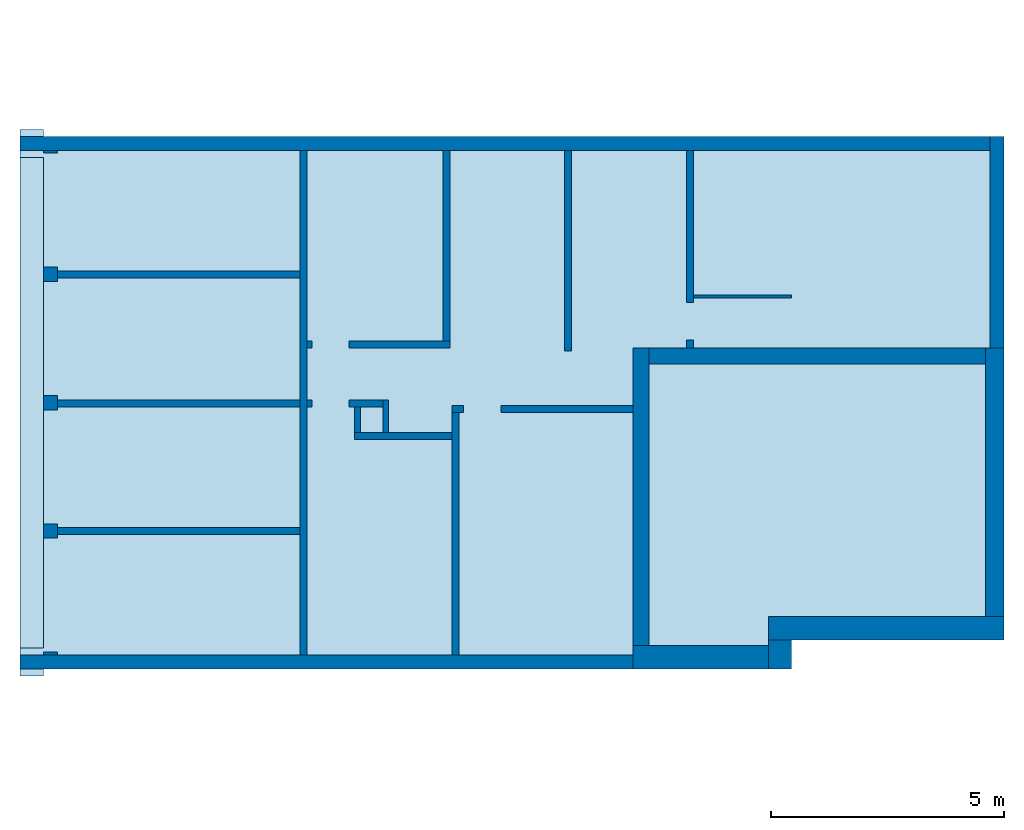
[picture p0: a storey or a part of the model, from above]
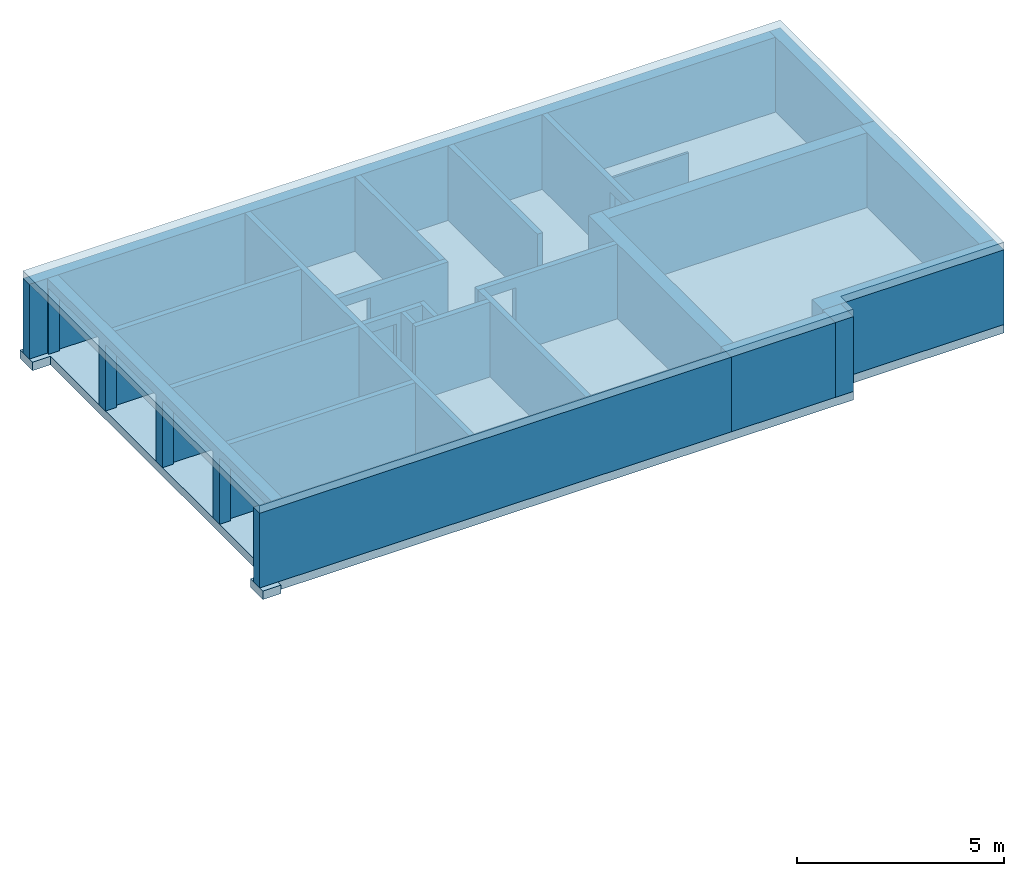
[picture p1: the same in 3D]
Properties of the parts of a building model (IFC2X3)

# File
Description: no view
File name: H.ifc
Time: 2026-08-27T15:52:09
Author: Besar Asani
Organization: No Organization
Written by: ODA SDAI 25.4
Authorization: b.asani

# IfcProject, 00'000 - Besar Asani
AllplanAttributes - Bauherr: Bauherr Name; Architekt: Architekt Name; Bauort: PLZ und Ort; Bauunternehmer Straße: Bauunternehmer Strasse; Bauunternehmer Plz/Ort: Bauunternehmer PLZ Ort; Bauherr Straße: Bauherr Strasse; Bauherr Plz/Ort: Bauherr PLZ Ort; Architekt Straße: Architekt Strasse; Architekt Plz/Ort: Architekt PLZ Ort; Projektbeschreibung: Projektbeschreibung; Bauunternehmer: Bauunternehmer Name

# IfcSite, Modelle auf dem Nullpunkt
RefLatitude: 48, 8, 10, 320000; RefLongitude: 11, 41, 19, 320000

# IfcBuildingStorey (2)
In: H
Elevation: 0 m
Name
UG
EG

# IfcBuildingElementProxy (2)
In: UG
AllplanAttributes - Objektname: Kontrollpunkt; Bezeichnung: Kontrollpunkt; Typ: Kontrollpunkt; Elementbezeichnung: Kontrollpunkt; Barrierefrei: no; öffentlich zugänglich: no; Attributset-Objekt: Body; Abrechnungsart: m³
BuildingElementProxyCommon - Status: Neubau; Tragendes Bauteil: no
Name | Text1 | Text2 | Allright_Bauteil_ID
Kontrollpunkt | X = 2695854.80 | Y = 1261037.75 | 7501Kop0000000102
Kontrollpunkt | X = 2695821.05 | Y = 1261022.70 | 7501Kop0000000104 | AllplanAttributes - X_Koordinate: 0 m; Y_Koordinate: 0 m; Achsenendpunkt (X): 0 m

# IfcOpeningElement: Opening (25)
AllplanAttributes - Object Layer Attributes #1, Türanschlag: -; Object Layer Attributes #1, Objektname: Türöffnung; Object Layer Attributes #1, Abrechnungsart: m³
Pset_OpeningElementCommon - FireExit: no
Name | In | Object Layer Attributes #1, Status | Object Layer Attributes #1, Versatz_oben = Object Layer Attributes #1, Versatz_unten | Object Layer Attributes #1, Gewerk | Object Layer Attributes #1, Allright_Bauteil_ID | ProtectedOpening
Türöffnung | UG | Bestand | 0 | Mauerarbeiten | 7501Fen0000000086 | no | AllplanAttributes - Object Layer Attributes #1, Bezeichnung: Türöffnung
Türöffnung | UG | Bestand | 0 | Mauerarbeiten | 7501Fen0000000092 | no | AllplanAttributes - Object Layer Attributes #1, Bezeichnung: Türöffnung
 | UG | Bestand | 0 | Mauerarbeiten | 7501Köf0000000073 | no
 | UG | Bestand |  | Mauerarbeiten | 7501Köf0000000047 | no
 | UG |  | 0 | Betonarbeiten | 7501Köf0000000009 | AllplanAttributes - Object Layer Attributes #1, Material: Béton; Object Layer Attributes #1, Tragendes Bauteil: yes; Object Layer Attributes #1, Attributset-Objekt: Door; Object Layer Attributes #1, Traduction matériau: Béton; Object Layer Attributes #1, DoorCommon, Status: Bestand; Object Layer Attributes #1, DoorCommon, Barrierefrei: no; Object Layer Attributes #1, DoorCommon, Rauchschutz: no; Object Layer Attributes #1, DoorCommon, Selbstschließend: no; Object Layer Attributes #1, DoorCommon, Antrieb: no
 | UG |  | 0 | Betonarbeiten | 7501Köf0000000015 | AllplanAttributes - Object Layer Attributes #1, Material: Béton; Object Layer Attributes #1, Tragendes Bauteil: yes; Object Layer Attributes #1, Attributset-Objekt: Door; Object Layer Attributes #1, Traduction matériau: Béton; Object Layer Attributes #1, DoorCommon, Status: Bestand; Object Layer Attributes #1, DoorCommon, Barrierefrei: no; Object Layer Attributes #1, DoorCommon, Rauchschutz: no; Object Layer Attributes #1, DoorCommon, Selbstschließend: no; Object Layer Attributes #1, DoorCommon, Antrieb: no
 | UG |  | 0 | Betonarbeiten | 7501Köf0000000006 | AllplanAttributes - Object Layer Attributes #1, Material: Béton; Object Layer Attributes #1, Tragendes Bauteil: yes; Object Layer Attributes #1, Attributset-Objekt: Door; Object Layer Attributes #1, Traduction matériau: Béton; Object Layer Attributes #1, DoorCommon, Status: Bestand; Object Layer Attributes #1, DoorCommon, Barrierefrei: no; Object Layer Attributes #1, DoorCommon, Rauchschutz: no; Object Layer Attributes #1, DoorCommon, Selbstschließend: no; Object Layer Attributes #1, DoorCommon, Antrieb: no
 | UG |  | 0 | Betonarbeiten | 7501Köf0000000012 | AllplanAttributes - Object Layer Attributes #1, Material: Béton; Object Layer Attributes #1, Tragendes Bauteil: yes; Object Layer Attributes #1, Attributset-Objekt: Door; Object Layer Attributes #1, Traduction matériau: Béton; Object Layer Attributes #1, DoorCommon, Status: Bestand; Object Layer Attributes #1, DoorCommon, Barrierefrei: no; Object Layer Attributes #1, DoorCommon, Rauchschutz: no; Object Layer Attributes #1, DoorCommon, Selbstschließend: no; Object Layer Attributes #1, DoorCommon, Antrieb: no
Türöffnung | EG | Bestand | 0 | Mauerarbeiten | 7502Fen0000000058 | no | AllplanAttributes - Object Layer Attributes #1, Bezeichnung: Türöffnung
Türöffnung | EG | Bestand | 0 | Mauerarbeiten | 7502Fen0000000069 | no | AllplanAttributes - Object Layer Attributes #1, Bezeichnung: Türöffnung
Türöffnung | EG | Bestand | 0 | Mauerarbeiten | 7502Fen0000000084 | no | AllplanAttributes - Object Layer Attributes #1, Bezeichnung: Türöffnung
Türöffnung | EG | Bestand | 0 | Mauerarbeiten | 7502Fen0000000101 | no | AllplanAttributes - Object Layer Attributes #1, Bezeichnung: Türöffnung
 | EG | Bestand | 0 | Mauerarbeiten | 7502Köf0000000042 | no
 | EG | Bestand | 0 | Mauerarbeiten | 7502Köf0000000026 | no
 | EG | Bestand | 0 | Mauerarbeiten | 7502Köf0000000141 | no
 | EG | Bestand | 0 | Mauerarbeiten | 7502Köf0000000136 | no
 | EG | Bestand | 0 | Mauerarbeiten | 7502Köf0000000009 | no
 | EG | Bestand | 0 | Mauerarbeiten | 7502Köf0000000113 | no
 | EG | Bestand | 0 | Mauerarbeiten | 7502Köf0000000108 | no
 | EG | Bestand | 0 | Mauerarbeiten | 7502Köf0000000121 | no
 | EG | Bestand | 0 | Mauerarbeiten | 7502Köf0000000037 | no
 | EG | Bestand | 0 | Mauerarbeiten | 7502Köf0000000126 | no
 | EG | Bestand | 0 | Mauerarbeiten | 7502Köf0000000094 | no
 | EG | Bestand | 0 | Mauerarbeiten | 7502Köf0000000065 | no
 | EG | Bestand | 0 | Mauerarbeiten | 7502Köf0000000131 | no

# IfcSlab (2)
In: UG
Material: Béton
AllplanAttributes - 2D Interaktion: yes; Gewerk: Betonarbeiten; Material: Béton; Traduction matériau: Béton; Abrechnungsart: m²
Pset_SlabCommon - LoadBearing: yes
Name | PredefinedType | Allright_Bauteil_ID | Objektname
 | FLOOR | 7501De 0000000099 | Decke | AllplanAttributes - Status: Bestand; Pset_SlabCommon - Combustible: no; Compartmentation: no
 | BASESLAB | 7501PFu0000000100 | Plattenfundament | AllplanAttributes - Aussenbauteil: yes; Attributset-Objekt: Slab; SlabCommon - Status: Bestand

# IfcWall (16)
AllplanAttributes - 2D Interaktion: yes; Höhe: 0 m; Objektname: Wand; Attributset-Objekt: Wall; Abrechnungsart: m³
Pset_WallCommon - Combustible: no; Compartmentation: no; ExtendToStructure: no
WallCommon - Status: Bestand
Name | In | Material = AllplanAttributes, Material = Traduction matériau | Gewerk | Länge (m) | Dicke (m) | Außenbauteil = LoadBearing | Allright_Bauteil_ID
 | UG | Brique | Mauerarbeiten | 4.23 | 0.15 | yes | 7501Kop0000000070 | AllplanAttributes - Abrechnungsart (2): St
 | UG | Brique | Mauerarbeiten | 3.88 | 0.15 | yes | 7501Kop0000000044 | AllplanAttributes - Abrechnungsart (2): St
Betonwand | UG | Béton | Betonarbeiten | 10.81 | 0.3 | yes | 7501Kop0000000003 | AllplanAttributes - Bezeichnung: Betonwand; Aussenbauteil: no
 | EG | Brique | Mauerarbeiten | 7.82 | 0.15 | yes | 7502Kop0000000039 | AllplanAttributes - Abrechnungsart (2): St
 | EG | Brique | Mauerarbeiten | 5.201 | 0.15 | yes | 7502Kop0000000023 | AllplanAttributes - Abrechnungsart (2): St
 | EG | Brique | Mauerarbeiten | 4.06 | 0.06 | no | 7502Kop0000000138 | AllplanAttributes - Kostentraeger: Typ_2
 | EG | Brique | Mauerarbeiten | 4.06 | 0.06 | no | 7502Kop0000000133 | AllplanAttributes - Kostentraeger: Typ_2
Betonwand | EG | Béton | Betonarbeiten | 20.28 | 0.3 | yes | 7502Kop0000000006 | AllplanAttributes - Bezeichnung: Betonwand; Aussenbauteil: no
 | EG | Brique | Mauerarbeiten | 2.68 | 0.06 | no | 7502Kop0000000110 | AllplanAttributes - Kostentraeger: Typ_2
 | EG | Brique | Mauerarbeiten | 1.575 | 0.06 | no | 7502Kop0000000105 | AllplanAttributes - Kostentraeger: Typ_2
 | EG | Brique | Mauerarbeiten | 4.06 | 0.06 | no | 7502Kop0000000118 | AllplanAttributes - Kostentraeger: Typ_2
 | EG | Brique | Mauerarbeiten | 8.97 | 0.15 | yes | 7502Kop0000000034 | AllplanAttributes - Abrechnungsart (2): St
 | EG | Brique | Mauerarbeiten | 4.9 | 0.06 | no | 7502Kop0000000123 | AllplanAttributes - Kostentraeger: Typ_2
 | EG | Brique | Mauerarbeiten | 2.7 | 0.06 | no | 7502Kop0000000091 | AllplanAttributes - Kostentraeger: Typ_2
 | EG | Brique | Mauerarbeiten | 3.71 | 0.15 | yes | 7502Kop0000000062 | AllplanAttributes - Abrechnungsart (2): St
 | EG | Brique | Mauerarbeiten | 4.61 | 0.06 | no | 7502Kop0000000128 | AllplanAttributes - Kostentraeger: Typ_2

# IfcWallStandardCase (43)
AllplanAttributes - Attributset-Objekt: Wall; Abrechnungsart: m³; Object Layer Attributes #1, 2D Interaktion: yes; Object Layer Attributes #1, Attributset-Objekt: Wall; Object Layer Attributes #1, Abrechnungsart: m³; Object Layer Attributes #1, Objektname: Wand; Object Layer Attributes #1, WallCommon, Status: Bestand; Object Layer Attributes #1, WallCommon, Brennbares Material: no; Object Layer Attributes #1, WallCommon, Brandabschnittsdefinierendes Bauteil: no; Object Layer Attributes #1, WallCommon, Raumhohe Wand: no
Pset_WallCommon - Combustible: no; Compartmentation: no; ExtendToStructure: no
WallCommon - Status: Bestand
Name | In | Material | Objektname | Allright_Bauteil_ID | Object Layer Attributes #1, Gewerk | Object Layer Attributes #1, Material = Object Layer Attributes #1, Traduction matériau | Object Layer Attributes #1, Außenbauteil = Object Layer Attributes #1, WallCommon, Tragendes Bauteil | Object Layer Attributes #1, Allright_Bauteil_ID | Abrechnungsart (2)
Betonwand | UG | Béton 0.3 m | Wand | 7501HWa0000000016 | Betonarbeiten | Béton | yes | 7501Wa 0000000017 | AllplanAttributes - Bezeichnung: Betonwand; Aussenbauteil: no; Pset_WallCommon - LoadBearing: yes
Betonwand | UG | Béton 0.3 m | Wand | 7501HWa0000000019 | Betonarbeiten | Béton | yes | 7501Wa 0000000020 | AllplanAttributes - Bezeichnung: Betonwand; Aussenbauteil: no; Pset_WallCommon - LoadBearing: yes
Betonwand | UG | Béton 0.5 m | Wand | 7501HWa0000000022 | Betonarbeiten | Béton | yes | 7501Wa 0000000023 | AllplanAttributes - Bezeichnung: Betonwand; Aussenbauteil: no; Pset_WallCommon - LoadBearing: yes
Betonwand | UG | Béton 0.5 m | Wand | 7501HWa0000000025 | Betonarbeiten | Béton | yes | 7501Wa 0000000026 | AllplanAttributes - Bezeichnung: Betonwand; Aussenbauteil: no; Pset_WallCommon - LoadBearing: yes
Betonwand | UG | Béton 0.35 m | Wand | 7501HWa0000000028 | Betonarbeiten | Béton | yes | 7501Wa 0000000029 | AllplanAttributes - Bezeichnung: Betonwand; Aussenbauteil: no; Pset_WallCommon - LoadBearing: yes
Betonwand | UG | Béton 0.4 m | Wand | 7501HWa0000000031 | Betonarbeiten | Béton | yes | 7501Wa 0000000032 | AllplanAttributes - Bezeichnung: Betonwand; Aussenbauteil: no; Pset_WallCommon - LoadBearing: yes
Betonwand | UG | Béton 0.5 m | Wand | 7501HWa0000000034 | Betonarbeiten | Béton | yes | 7501Wa 0000000035 | AllplanAttributes - Bezeichnung: Betonwand; Aussenbauteil: no; Pset_WallCommon - LoadBearing: yes
Betonwand | UG | Béton 0.3 m | Wand | 7501HWa0000000037 | Betonarbeiten | Béton | yes | 7501Wa 0000000038 | AllplanAttributes - Bezeichnung: Betonwand; Aussenbauteil: no; Pset_WallCommon - LoadBearing: yes
Betonwand | UG | Béton 0.35 m | Wand | 7501HWa0000000040 | Betonarbeiten | Béton | yes | 7501Wa 0000000041 | AllplanAttributes - Bezeichnung: Betonwand; Aussenbauteil: no; Pset_WallCommon - LoadBearing: yes
 | UG | Brique 0.15 m | Mehrsch-Wand | 7501HWa0000000048 | Mauerarbeiten | Brique | yes | 7501Wa 0000000049 | St
 | UG | Brique 0.15 m | Mehrsch-Wand | 7501HWa0000000051 | Mauerarbeiten | Brique | yes | 7501Wa 0000000052 | St
 | UG | Brique 0.15 m | Mehrsch-Wand | 7501HWa0000000054 | Mauerarbeiten | Brique | yes | 7501Wa 0000000055 | St
 | UG | Brique 0.15 m | Mehrsch-Wand | 7501HWa0000000057 | Mauerarbeiten | Brique | yes | 7501Wa 0000000058 | St
 | UG | Brique 0.15 m | Mehrsch-Wand | 7501HWa0000000060 | Mauerarbeiten | Brique | yes | 7501Wa 0000000061 | St
 | UG | Brique 0.15 m | Mehrsch-Wand | 7501HWa0000000063 | Mauerarbeiten | Brique | yes | 7501Wa 0000000064 | St
 | UG | Brique 0.15 m | Mehrsch-Wand | 7501HWa0000000066 | Mauerarbeiten | Brique | yes | 7501Wa 0000000067 | St
 | UG | Brique 0.12 m | Mehrsch-Wand | 7501HWa0000000074 | Mauerarbeiten | Brique | yes | 7501Wa 0000000075 | St
 | UG | Brique 0.12 m | Mehrsch-Wand | 7501HWa0000000077 | Mauerarbeiten | Brique | yes | 7501Wa 0000000078 | St
 | UG | Brique 0.15 m | Mehrsch-Wand | 7501HWa0000000080 | Mauerarbeiten | Brique | yes | 7501Wa 0000000081 | St
 | UG | Brique 0.15 m | Mehrsch-Wand | 7501HWa0000000083 | Mauerarbeiten | Brique | yes | 7501Wa 0000000084 | St
 | UG | Brique 0.15 m | Mehrsch-Wand | 7501HWa0000000089 | Mauerarbeiten | Brique | yes | 7501Wa 0000000090 | St
 | UG | Brique 0.06 m | Mehrsch-Wand | 7501HWa0000000095 | Mauerarbeiten | Brique | no | 7501Wa 0000000096 | AllplanAttributes - Object Layer Attributes #1, Kostentraeger: Typ_2
Betonwand | EG | Béton 0.3 m | Wand | 7502HWa0000000002 | Betonarbeiten | Béton | yes | 7502Wa 0000000003 | AllplanAttributes - Bezeichnung: Betonwand; Aussenbauteil: no; Pset_WallCommon - LoadBearing: yes
Betonwand | EG | Béton 0.3 m | Wand | 7502HWa0000000010 | Betonarbeiten | Béton | yes | 7502Wa 0000000011 | AllplanAttributes - Bezeichnung: Betonwand; Aussenbauteil: no; Pset_WallCommon - LoadBearing: yes
Betonwand | EG | Béton 0.3 m | Wand | 7502HWa0000000013 | Betonarbeiten | Béton | yes | 7502Wa 0000000014 | AllplanAttributes - Bezeichnung: Betonwand; Aussenbauteil: no; Pset_WallCommon - LoadBearing: yes
Betonwand | EG | Béton 0.3 m | Wand | 7502HWa0000000016 | Betonarbeiten | Béton | yes | 7502Wa 0000000017 | AllplanAttributes - Bezeichnung: Betonwand; Aussenbauteil: no; Pset_WallCommon - LoadBearing: yes
Betonwand | EG | Béton 0.3 m | Wand | 7502HWa0000000019 | Betonarbeiten | Béton | yes | 7502Wa 0000000020 | AllplanAttributes - Bezeichnung: Betonwand; Aussenbauteil: no; Pset_WallCommon - LoadBearing: yes
 | EG | Brique 0.15 m | Mehrsch-Wand | 7502HWa0000000027 | Mauerarbeiten | Brique | yes | 7502Wa 0000000028 | St
 | EG | Brique 0.15 m | Mehrsch-Wand | 7502HWa0000000030 | Mauerarbeiten | Brique | yes | 7502Wa 0000000031 | St
 | EG | Brique 0.15 m | Mehrsch-Wand | 7502HWa0000000043 | Mauerarbeiten | Brique | yes | 7502Wa 0000000044 | St
 | EG | Brique 0.15 m | Mehrsch-Wand | 7502HWa0000000046 | Mauerarbeiten | Brique | yes | 7502Wa 0000000047 | St
 | EG | Brique 0.15 m | Mehrsch-Wand | 7502HWa0000000049 | Mauerarbeiten | Brique | yes | 7502Wa 0000000050 | St
 | EG | Brique 0.15 m | Mehrsch-Wand | 7502HWa0000000052 | Mauerarbeiten | Brique | yes | 7502Wa 0000000053 | St
 | EG | Brique 0.15 m | Mehrsch-Wand | 7502HWa0000000055 | Mauerarbeiten | Brique | yes | 7502Wa 0000000056 | St
 | EG | Brique 0.15 m | Mehrsch-Wand | 7502HWa0000000066 | Mauerarbeiten | Brique | yes | 7502Wa 0000000067 | St
 | EG | Brique 0.15 m | Mehrsch-Wand | 7502HWa0000000072 | Mauerarbeiten | Brique | yes | 7502Wa 0000000073 | St
 | EG | Brique 0.15 m | Mehrsch-Wand | 7502HWa0000000075 | Mauerarbeiten | Brique | yes | 7502Wa 0000000076 | St
 | EG | Brique 0.15 m | Mehrsch-Wand | 7502HWa0000000078 | Mauerarbeiten | Brique | yes | 7502Wa 0000000079 | St
 | EG | Brique 0.15 m | Mehrsch-Wand | 7502HWa0000000081 | Mauerarbeiten | Brique | yes | 7502Wa 0000000082 | St
 | EG | Brique 0.06 m | Mehrsch-Wand | 7502HWa0000000087 | Mauerarbeiten | Brique | no | 7502Wa 0000000088 | AllplanAttributes - Object Layer Attributes #1, Kostentraeger: Typ_2
 | EG | Brique 0.06 m | Mehrsch-Wand | 7502HWa0000000095 | Mauerarbeiten | Brique | no | 7502Wa 0000000096 | AllplanAttributes - Object Layer Attributes #1, Kostentraeger: Typ_2
 | EG | Brique 0.06 m | Mehrsch-Wand | 7502HWa0000000098 | Mauerarbeiten | Brique | no | 7502Wa 0000000099 | AllplanAttributes - Object Layer Attributes #1, Kostentraeger: Typ_2
 | EG | Brique 0.06 m | Mehrsch-Wand | 7502HWa0000000114 | Mauerarbeiten | Brique | no | 7502Wa 0000000115 | AllplanAttributes - Object Layer Attributes #1, Kostentraeger: Typ_2
